One B-rep face of a CAD part: STEP entity #166.
In plain terms, the planar face has unit normal (-1, 0, 0).
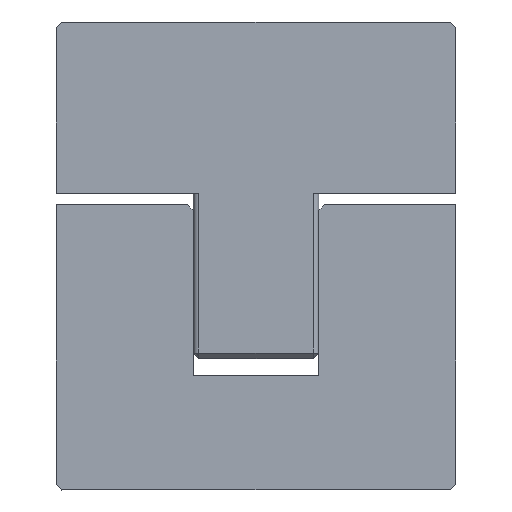
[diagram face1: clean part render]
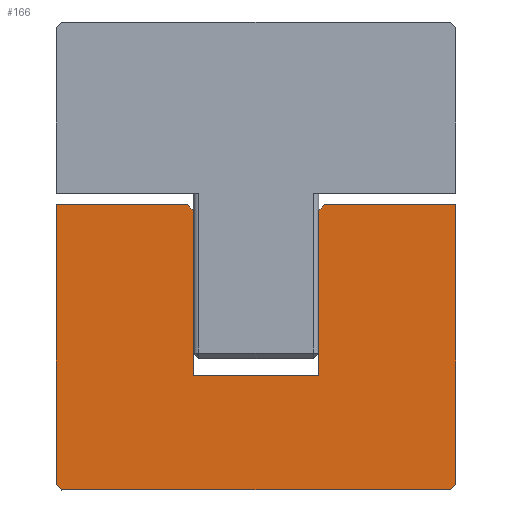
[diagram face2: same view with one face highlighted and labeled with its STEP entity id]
Its self-contained STEP definition (entity closure, numbers rounded to 3 decimals):
#63=CARTESIAN_POINT('Axis2P3D Location',(-13.,0.,0.)) ;
#68=CARTESIAN_POINT('Line Origine',(-13.,17.25,5.5)) ;
#72=CARTESIAN_POINT('Vertex',(-13.,10.,5.5)) ;
#74=CARTESIAN_POINT('Vertex',(-13.,24.5,5.5)) ;
#77=CARTESIAN_POINT('Line Origine',(-13.,10.,0.)) ;
#81=CARTESIAN_POINT('Vertex',(-13.,10.,-5.5)) ;
#84=CARTESIAN_POINT('Line Origine',(-13.,17.25,-5.5)) ;
#88=CARTESIAN_POINT('Vertex',(-13.,24.5,-5.5)) ;
#91=CARTESIAN_POINT('Line Origine',(-13.,24.75,-5.75)) ;
#95=CARTESIAN_POINT('Vertex',(-13.,25.,-6.)) ;
#98=CARTESIAN_POINT('Line Origine',(-13.,25.,-11.75)) ;
#102=CARTESIAN_POINT('Vertex',(-13.,25.,-17.5)) ;
#105=CARTESIAN_POINT('Line Origine',(-13.,12.75,-17.5)) ;
#109=CARTESIAN_POINT('Vertex',(-13.,0.5,-17.5)) ;
#112=CARTESIAN_POINT('Line Origine',(-13.,0.25,-17.25)) ;
#116=CARTESIAN_POINT('Vertex',(-13.,0.,-17.)) ;
#119=CARTESIAN_POINT('Line Origine',(-13.,0.,0.)) ;
#123=CARTESIAN_POINT('Vertex',(-13.,0.,17.)) ;
#126=CARTESIAN_POINT('Line Origine',(-13.,0.25,17.25)) ;
#130=CARTESIAN_POINT('Vertex',(-13.,0.5,17.5)) ;
#133=CARTESIAN_POINT('Line Origine',(-13.,12.75,17.5)) ;
#137=CARTESIAN_POINT('Vertex',(-13.,25.,17.5)) ;
#140=CARTESIAN_POINT('Line Origine',(-13.,25.,11.75)) ;
#144=CARTESIAN_POINT('Vertex',(-13.,25.,6.)) ;
#147=CARTESIAN_POINT('Line Origine',(-13.,24.75,5.75)) ;
#64=DIRECTION('Axis2P3D Direction',(1.,0.,0.)) ;
#65=DIRECTION('Axis2P3D XDirection',(0.,0.,-1.)) ;
#69=DIRECTION('Vector Direction',(0.,1.,0.)) ;
#78=DIRECTION('Vector Direction',(0.,0.,1.)) ;
#85=DIRECTION('Vector Direction',(0.,-1.,0.)) ;
#92=DIRECTION('Vector Direction',(0.,0.707,-0.707)) ;
#99=DIRECTION('Vector Direction',(0.,0.,1.)) ;
#106=DIRECTION('Vector Direction',(0.,1.,0.)) ;
#113=DIRECTION('Vector Direction',(0.,-0.707,0.707)) ;
#120=DIRECTION('Vector Direction',(0.,0.,-1.)) ;
#127=DIRECTION('Vector Direction',(0.,0.707,0.707)) ;
#134=DIRECTION('Vector Direction',(0.,-1.,0.)) ;
#141=DIRECTION('Vector Direction',(0.,0.,1.)) ;
#148=DIRECTION('Vector Direction',(0.,-0.707,-0.707)) ;
#66=AXIS2_PLACEMENT_3D('Plane Axis2P3D',#63,#64,#65) ;
#153=ORIENTED_EDGE('',*,*,#76,.F.) ;
#154=ORIENTED_EDGE('',*,*,#83,.F.) ;
#155=ORIENTED_EDGE('',*,*,#90,.F.) ;
#156=ORIENTED_EDGE('',*,*,#97,.T.) ;
#157=ORIENTED_EDGE('',*,*,#104,.F.) ;
#158=ORIENTED_EDGE('',*,*,#111,.F.) ;
#159=ORIENTED_EDGE('',*,*,#118,.T.) ;
#160=ORIENTED_EDGE('',*,*,#125,.F.) ;
#161=ORIENTED_EDGE('',*,*,#132,.T.) ;
#162=ORIENTED_EDGE('',*,*,#139,.F.) ;
#163=ORIENTED_EDGE('',*,*,#146,.F.) ;
#164=ORIENTED_EDGE('',*,*,#151,.T.) ;
#70=VECTOR('Line Direction',#69,1.) ;
#79=VECTOR('Line Direction',#78,1.) ;
#86=VECTOR('Line Direction',#85,1.) ;
#93=VECTOR('Line Direction',#92,1.) ;
#100=VECTOR('Line Direction',#99,1.) ;
#107=VECTOR('Line Direction',#106,1.) ;
#114=VECTOR('Line Direction',#113,1.) ;
#121=VECTOR('Line Direction',#120,1.) ;
#128=VECTOR('Line Direction',#127,1.) ;
#135=VECTOR('Line Direction',#134,1.) ;
#142=VECTOR('Line Direction',#141,1.) ;
#149=VECTOR('Line Direction',#148,1.) ;
#166=ADVANCED_FACE('MANIFOLD_SOLID_BREP #858',(#165),#67,.F.) ;
#76=EDGE_CURVE('',#73,#75,#71,.T.) ;
#83=EDGE_CURVE('',#82,#73,#80,.T.) ;
#90=EDGE_CURVE('',#89,#82,#87,.T.) ;
#97=EDGE_CURVE('',#89,#96,#94,.T.) ;
#104=EDGE_CURVE('',#103,#96,#101,.T.) ;
#111=EDGE_CURVE('',#110,#103,#108,.T.) ;
#118=EDGE_CURVE('',#110,#117,#115,.T.) ;
#125=EDGE_CURVE('',#124,#117,#122,.T.) ;
#132=EDGE_CURVE('',#124,#131,#129,.T.) ;
#139=EDGE_CURVE('',#138,#131,#136,.T.) ;
#146=EDGE_CURVE('',#145,#138,#143,.T.) ;
#151=EDGE_CURVE('',#145,#75,#150,.T.) ;
#152=EDGE_LOOP('',(#153,#154,#155,#156,#157,#158,#159,#160,#161,#162,#163,#164)) ;
#165=FACE_OUTER_BOUND('',#152,.T.) ;
#71=LINE('Line',#68,#70) ;
#80=LINE('Line',#77,#79) ;
#87=LINE('Line',#84,#86) ;
#94=LINE('Line',#91,#93) ;
#101=LINE('Line',#98,#100) ;
#108=LINE('Line',#105,#107) ;
#115=LINE('Line',#112,#114) ;
#122=LINE('Line',#119,#121) ;
#129=LINE('Line',#126,#128) ;
#136=LINE('Line',#133,#135) ;
#143=LINE('Line',#140,#142) ;
#150=LINE('Line',#147,#149) ;
#67=PLANE('Plane',#66) ;
#73=VERTEX_POINT('',#72) ;
#75=VERTEX_POINT('',#74) ;
#82=VERTEX_POINT('',#81) ;
#89=VERTEX_POINT('',#88) ;
#96=VERTEX_POINT('',#95) ;
#103=VERTEX_POINT('',#102) ;
#110=VERTEX_POINT('',#109) ;
#117=VERTEX_POINT('',#116) ;
#124=VERTEX_POINT('',#123) ;
#131=VERTEX_POINT('',#130) ;
#138=VERTEX_POINT('',#137) ;
#145=VERTEX_POINT('',#144) ;
